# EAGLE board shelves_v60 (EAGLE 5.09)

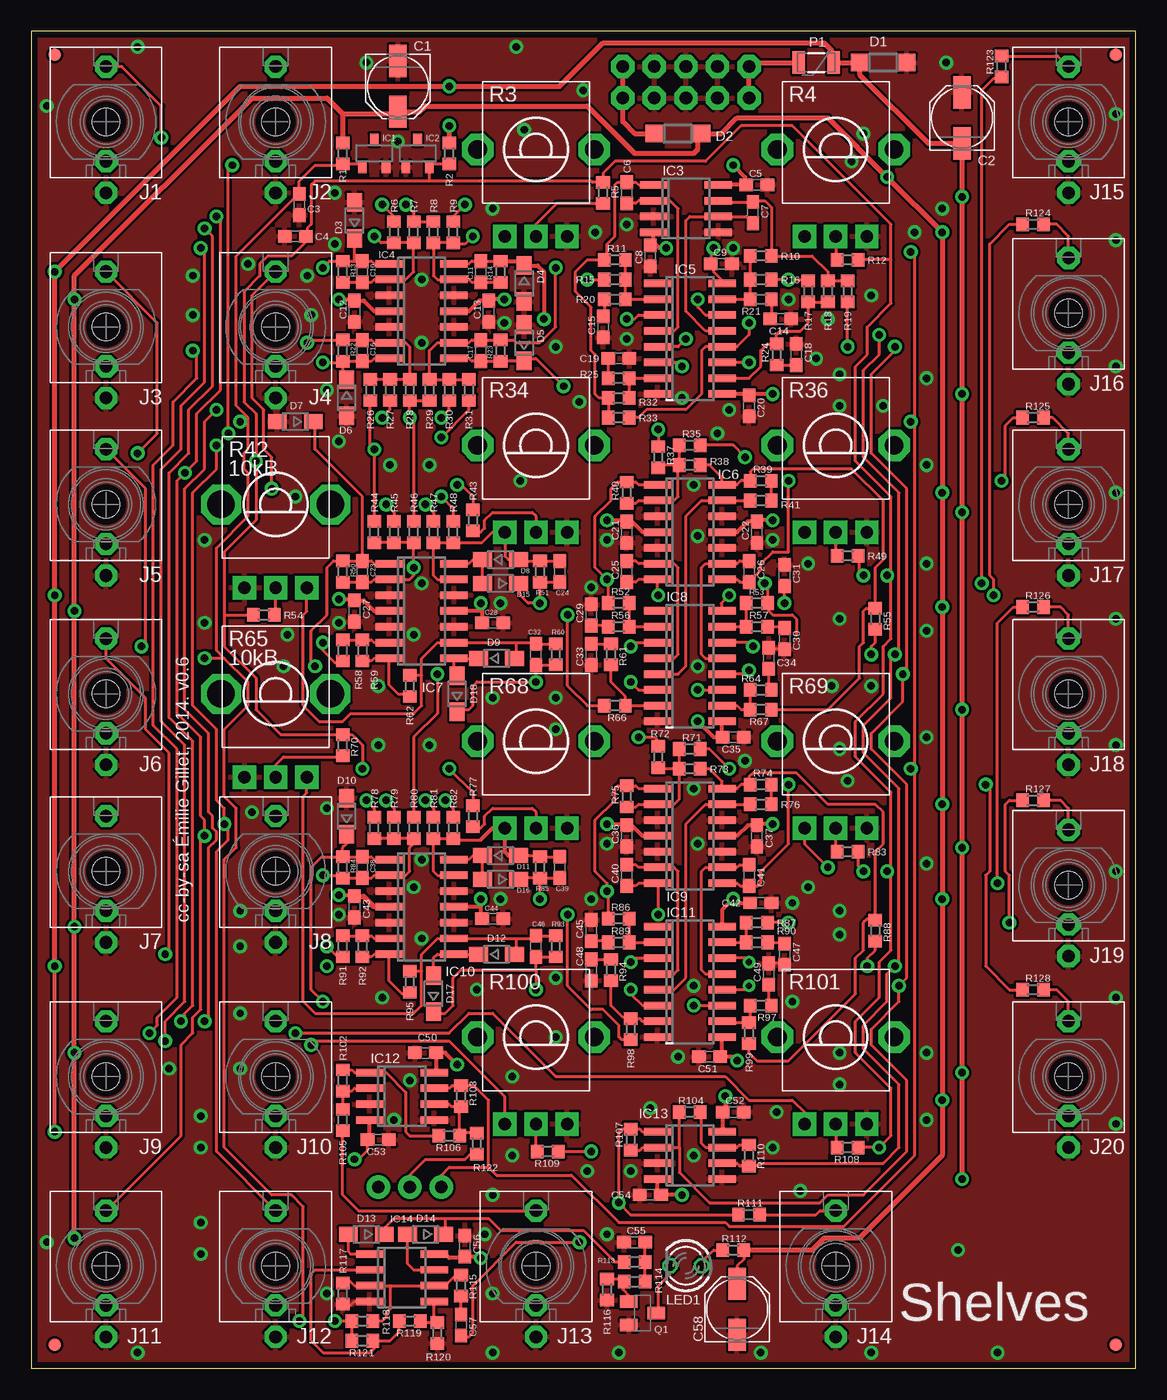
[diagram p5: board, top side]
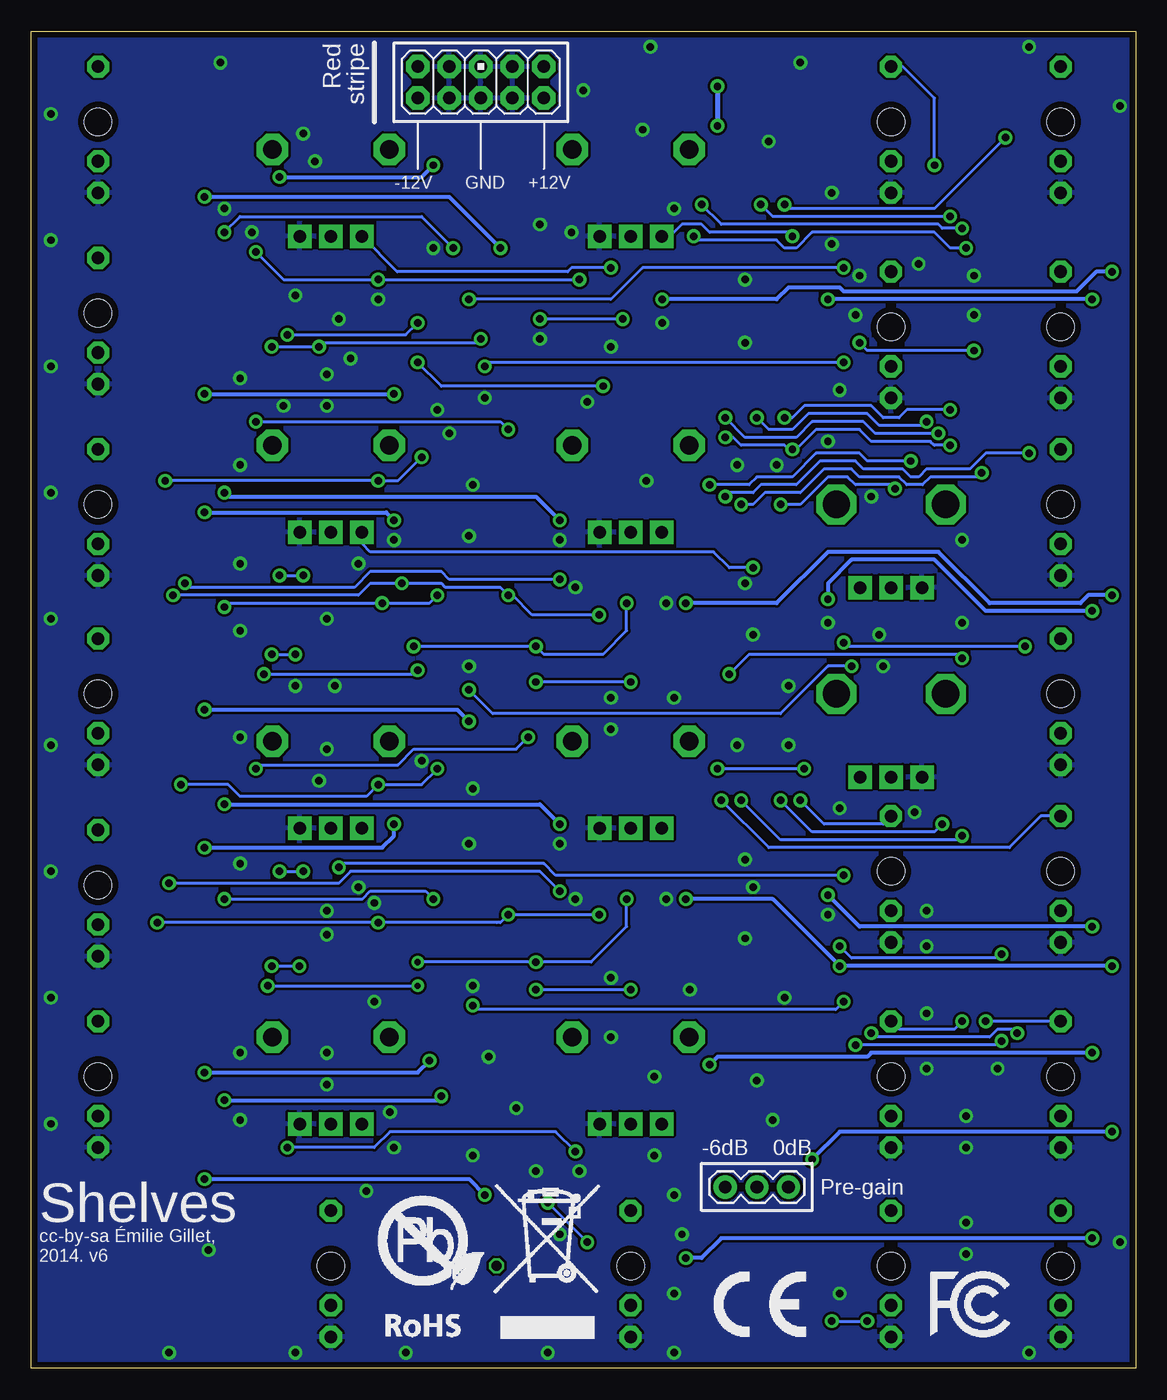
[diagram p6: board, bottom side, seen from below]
Size 88.9 x 107.63 mm. Coordinates in mm from the lower left corner, seen from the top.
Outline: 0,0 88.9,0 88.9,107.63 0,107.63 0,0
Copper layers (1*16): Top 0.035mm / dielectric 1.5mm / Bottom 0.035mm
Design rules "PCBCart-Standard": minimum track width 8mil, minimum drill 0.4mm, track to track 8mil, track to pad 8mil, pad to pad 8mil, via to via 8mil, smd to smd 8mil, copper to edge 20mil, drill to drill 8mil, minimum pad ring 8mil, minimum via ring 10mil, stop-mask expansion 3mil, vias tented up to drill 25mil, thermal gap 8mil

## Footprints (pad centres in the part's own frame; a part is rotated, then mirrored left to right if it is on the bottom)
PANASONIC_C = smd 2.6 x 1.4: + 2.05,0; - -2.05,0
C0603 = smd 1.1 x 1: 1 -0.85,0; 2 0.85,0
SOD123 = smd 1.4 x 1.4: A 1.9,0; C -1.9,0
SOD323-W = smd 1.5 x 1.2: A 1.45,0; C -1.45,0
DBZ_R-PDSO-G3 = smd 0.7 x 1: 1 -0.95,-1.1; 2 0.95,-1.1; 3 0,1.1
SO08 = smd 0.6 x 2.2: 1 -1.905,-2.6; 2 -0.635,-2.6; 3 0.635,-2.6; 4 1.905,-2.6; 5 1.905,2.6; 6 0.635,2.6; 7 -0.635,2.6; 8 -1.905,2.6
SO14 = smd 0.6 x 2.2: 1 -3.81,-2.6; 2 -2.54,-2.6; 3 -1.27,-2.6; 4 0,-2.6; 5 1.27,-2.6; 6 2.54,-2.6; 7 3.81,-2.6; 8 3.81,2.6; 9 2.54,2.6; 10 1.27,2.6; 11 0,2.6; 12 -1.27,2.6; 13 -2.54,2.6; 14 -3.81,2.6
SOIC16N = smd 0.6 x 2.2: 1 -4.445,-2.6; 2 -3.175,-2.6; 3 -1.905,-2.6; 4 -0.635,-2.6; 5 0.635,-2.6; 6 1.905,-2.6; 7 3.175,-2.6; 8 4.445,-2.6; 9 4.445,2.6; 10 3.175,2.6; 11 1.905,2.6; 12 0.635,2.6; 13 -0.635,2.6; 14 -1.905,2.6; 15 -3.175,2.6; 16 -4.445,2.6
WQP_PJ_301M6 = drill 1.016 pad 1.778 octagon: P1 0,-5.715; P2 0,-3.175; P3 0,4.445 | hole 2.2: 0,0
FIDUCIAL-1X2 = smd 1 x 1: 1 0,0
1X03 = drill 1.016 pad 1.88 round: 1 0,0; 2 2.54,0; 3 5.08,0
AVR_ICSP = drill 1.016 pad 1.88 octagon: 1 -1.27,5.08; 2 1.27,5.08; 3 -1.27,2.54; 4 1.27,2.54; 5 -1.27,0; 6 1.27,0; 7 -1.27,-2.54; 8 1.27,-2.54; 9 -1.27,-5.08; 10 1.27,-5.08
LED3MM = drill 0.813 octagon: A -1.27,0; K 1.27,0
PTC-1206 = smd 1 x 1.8: 1 -1.4,0; 2 1.4,0
SOT23-BEC = smd 1 x 1.4: B -0.95,-1.1; C 0,1.1; E 0.95,-1.1
R0603 = smd 1 x 1.1: 1 -0.85,0; 2 0.85,0
ALPS_POT_VERTICAL_PS = drill 1 pad 1.88 square: P$1 -2.5,7; P$2 0,7; P$3 2.5,7 | drill 1.5 pad 2.54 octagon: P$4 -4.7,0; P$5 4.7,0
ALPS_POT_VERTICAL = drill 1 pad 1.88 square: P$1 -2.5,6.7; P$2 0,6.7; P$3 2.5,6.7 | drill 2.2 pad 3.175 octagon: P$4 -4.4,0; P$5 4.4,0

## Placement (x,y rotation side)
C1  22u  [PANASONIC_C]  29.53,103.19 270 top
C2  22u  [PANASONIC_C]  74.93,100.65 90 top
C3  100n  [C0603]  21.59,93.66 270 top
C4  100n  [C0603]  21.27,91.12 180 top
C5  100n  [C0603]  58.42,95.25 0 top
C6  68p  [C0603]  47.94,94.61 90 top
C7  68p  [C0603]  58.1,93.03 90 top
C8  100n  [C0603]  49.85,89.53 90 top
C9  100n  [C0603]  55.56,88.9 0 top
C10  560p  [C0603]  26.67,88.27 270 top
C11  560p  [C0603]  36.2,88.27 270 top
C12  100n  [C0603]  26.04,85.09 270 top
C13  100n  [C0603]  36.83,85.09 90 top
C14  560p  [C0603]  60.33,84.45 0 top
C15  560p  [C0603]  46.04,83.82 270 top
C16  560p  [C0603]  26.67,81.92 90 top
C17  560p  [C0603]  36.2,81.92 90 top
C18  560p  [C0603]  61.59,81.6 90 top
C19  560p  [C0603]  47.31,81.28 0 top
C20  100n  [C0603]  57.79,77.47 90 top
C21  100n  [C0603]  47.94,67.31 270 top
C22  100n  [C0603]  58.42,67.31 90 top
C23  560p  [C0603]  26.67,64.14 270 top
C24  560p  [C0603]  42.55,64.14 90 top
C25  68p  [C0603]  47.94,64.14 270 top
C26  68p  [C0603]  57.79,64.14 270 top
C27  100n  [C0603]  26.04,60.96 270 top
C28  100n  [C0603]  37.15,60.01 180 top
C29  560p  [C0603]  45.09,60.64 90 top
C30  560p  [C0603]  60.64,58.74 270 top
C31  100n  [C0603]  60.64,63.82 90 top
C32  560p  [C0603]  40.64,57.47 90 top
C33  560p  [C0603]  45.09,57.47 270 top
C34  560p  [C0603]  59.37,57.15 90 top
C35  100n  [C0603]  56.52,50.8 180 top
C36  100n  [C0603]  47.94,42.86 270 top
C37  100n  [C0603]  58.42,42.86 90 top
C38  560p  [C0603]  26.67,40.32 270 top
C39  560p  [C0603]  42.55,40.32 90 top
C40  68p  [C0603]  47.94,39.69 270 top
C41  68p  [C0603]  57.79,39.69 270 top
C42  100n  [C0603]  58.74,37.47 0 top
C43  100n  [C0603]  26.04,37.15 270 top
C44  100n  [C0603]  37.15,36.2 180 top
C45  560p  [C0603]  45.09,35.24 90 top
C46  560p  [C0603]  40.64,33.97 90 top
C47  560p  [C0603]  60.64,33.34 270 top
C48  560p  [C0603]  45.09,32.07 270 top
C49  560p  [C0603]  59.37,31.75 90 top
C50  100n  [C0603]  31.75,25.4 180 top
C51  100n  [C0603]  54.61,25.08 0 top
C52  100n  [C0603]  56.52,20.64 0 top
C53  100n  [C0603]  27.94,18.41 180 top
C54  100n  [C0603]  49.85,13.97 0 top
C55  100n  [C0603]  48.58,10.16 180 top
C56  100n  [C0603]  34.93,9.84 90 top
C57  100n  [C0603]  34.61,3.49 270 top
C58  22u  [PANASONIC_C]  56.83,4.76 90 top
D1  1N5819HW  [SOD123]  68.58,105.09 180 top
D2  1N5819HW  [SOD123]  52.07,99.38 180 top
D3  1N4148  [SOD323-W]  26.04,92.39 90 top
D4  1N4148  [SOD323-W]  39.69,87.31 270 top
D5  1N4148  [SOD323-W]  39.69,82.55 90 top
D6  1N4148  [SOD323-W]  25.4,78.11 270 top
D7  1N4148  [SOD323-W]  21.27,76.2 180 top
D8  1N4148  [SOD323-W]  37.78,65.09 0 top
D9  1N4148  [SOD323-W]  37.47,57.15 0 top
D10  1N4148  [SOD323-W]  25.4,44.45 90 top
D11  1N4148  [SOD323-W]  37.78,41.27 0 top
D12  1N4148  [SOD323-W]  37.47,33.34 0 top
D13  1N4148  [SOD323-W]  26.99,10.79 180 top
D14  1N4148  [SOD323-W]  31.75,10.79 180 top
D15  1N4148  [SOD323-W]  37.78,63.18 180 top
D16  1N4148  [SOD323-W]  37.78,39.37 180 top
D17  1N4148  [SOD323-W]  32.38,30.16 90 top
D18  1N4148  [SOD323-W]  34.29,54.29 90 top
IC1  LM4040B10  [DBZ_R-PDSO-G3]  27.62,97.79 0 top
IC2  LM4040B10  [DBZ_R-PDSO-G3]  31.12,97.79 0 top
IC3  TL072D  [SO08]  52.7,93.34 270 top
IC4  TL074D  [SO14]  31.43,85.09 270 top
IC5  V2164SZ  [SOIC16N]  53.02,82.87 270 top
IC6  TL074D  [SO14]  53.02,67.31 270 top
IC7  TL074D  [SO14]  31.43,60.96 270 top
IC8  V2164SZ  [SOIC16N]  53.02,56.52 270 top
IC9  TL074D  [SO14]  53.02,42.86 270 top
IC10  TL074D  [SO14]  31.43,37.15 270 top
IC11  V2164SZ  [SOIC16N]  53.02,31.11 270 top
IC12  TL072D  [SO08]  29.85,21.91 270 top
IC13  TL072D  [SO08]  53.02,17.14 270 top
IC14  TL072D  [SO08]  29.85,7.3 270 top
J1  PJ301_THONKICONN6  [WQP_PJ_301M6]  6.03,100.33 0 top
J2  PJ301_THONKICONN6  [WQP_PJ_301M6]  19.69,100.33 0 top
J3  PJ301_THONKICONN6  [WQP_PJ_301M6]  6.03,83.82 0 top
J4  PJ301_THONKICONN6  [WQP_PJ_301M6]  19.69,83.82 0 top
J5  PJ301_THONKICONN6  [WQP_PJ_301M6]  6.03,69.53 0 top
J6  PJ301_THONKICONN6  [WQP_PJ_301M6]  6.03,54.29 0 top
J7  PJ301_THONKICONN6  [WQP_PJ_301M6]  6.03,40.01 0 top
J8  PJ301_THONKICONN6  [WQP_PJ_301M6]  19.69,40.01 0 top
J9  PJ301_THONKICONN6  [WQP_PJ_301M6]  6.03,23.5 0 top
J10  PJ301_THONKICONN6  [WQP_PJ_301M6]  19.69,23.5 0 top
J11  PJ301_THONKICONN6  [WQP_PJ_301M6]  6.03,8.26 0 top
J12  PJ301_THONKICONN6  [WQP_PJ_301M6]  19.69,8.26 0 top
J13  PJ301_THONKICONN6  [WQP_PJ_301M6]  40.64,8.26 0 top
J14  PJ301_THONKICONN6  [WQP_PJ_301M6]  64.77,8.26 0 top
J15  PJ301_THONKICONN6  [WQP_PJ_301M6]  83.5,100.33 0 top
J16  PJ301_THONKICONN6  [WQP_PJ_301M6]  83.5,84.93 0 top
J17  PJ301_THONKICONN6  [WQP_PJ_301M6]  83.5,69.53 0 top
J18  PJ301_THONKICONN6  [WQP_PJ_301M6]  83.5,54.29 0 top
J19  PJ301_THONKICONN6  [WQP_PJ_301M6]  83.5,38.89 0 top
J20  PJ301_THONKICONN6  [WQP_PJ_301M6]  83.5,23.5 0 top
JP1  FIDUCIAL1X2  [FIDUCIAL-1X2]  1.91,105.73 0 top
JP2  FIDUCIAL1X2  [FIDUCIAL-1X2]  87.31,105.73 0 top
JP3  FIDUCIAL1X2  [FIDUCIAL-1X2]  1.91,1.91 0 top
JP4  FIDUCIAL1X2  [FIDUCIAL-1X2]  87.31,1.91 0 top
JP5  [1X03]  27.94,14.61 180 bottom
JP11  M05X2PTH  [AVR_ICSP]  52.7,103.5 270 bottom
LED1  WP-710A10GD  [LED3MM]  52.7,8.26 180 top
P1  PTCSMD  [PTC-1206]  63.18,105.09 180 top
Q1  MMBT3904  [SOT23-BEC]  49.21,4.45 270 top
R1  3.3k  [R0603]  25.08,97.79 270 top
R2  1.0k  [R0603]  33.66,97.79 270 top
R3  10kB  [ALPS_POT_VERTICAL_PS]  40.64,98.11 180 top
R4  10kB  [ALPS_POT_VERTICAL_PS]  64.77,98.11 180 top
R5  100k  [R0603]  46.04,94.61 270 top
R6  100k  [R0603]  29.21,91.44 270 top
R7  100k  [R0603]  30.8,91.44 270 top
R8  100k  [R0603]  32.38,91.44 270 top
R9  100k  [R0603]  33.97,91.44 270 top
R10  100k  [R0603]  58.74,89.53 0 top
R11  100k  [R0603]  46.99,89.22 180 top
R12  100k  [R0603]  65.72,89.22 180 top
R13  18k  [R0603]  25.08,88.27 90 top
R14  18k  [R0603]  37.78,88.27 90 top
R15  100k  [R0603]  46.99,87.63 0 top
R16  100k  [R0603]  58.74,87.63 180 top
R17  100k  [R0603]  62.55,86.68 270 top
R18  100k  [R0603]  64.13,86.68 270 top
R19  100k  [R0603]  65.72,86.68 270 top
R20  510  [R0603]  46.99,86.04 0 top
R21  510  [R0603]  58.74,86.04 180 top
R22  12k  [R0603]  25.08,81.92 270 top
R23  12k  [R0603]  37.78,81.92 270 top
R24  510  [R0603]  60.01,81.6 90 top
R25  510  [R0603]  47.31,79.69 0 top
R26  120k  [R0603]  27.3,78.74 90 top
R27  120k  [R0603]  28.89,78.74 90 top
R28  200k  [R0603]  30.48,78.74 90 top
R29  200k  [R0603]  32.07,78.74 90 top
R30  120k  [R0603]  33.66,78.74 90 top
R31  120k  [R0603]  35.24,78.74 90 top
R32  100k  [R0603]  47.31,78.11 0 top
R33  100k  [R0603]  47.31,76.52 0 top
R34  10kB  [ALPS_POT_VERTICAL_PS]  40.64,74.3 180 top
R35  100k  [R0603]  53.02,74.3 0 top
R36  10kB  [ALPS_POT_VERTICAL_PS]  64.77,74.3 180 top
R37  100k  [R0603]  50.48,73.34 270 top
R38  100k  [R0603]  53.02,72.71 0 top
R39  100k  [R0603]  58.74,71.44 0 top
R40  100k  [R0603]  47.94,70.48 90 top
R41  100k  [R0603]  58.74,69.85 180 top
R42  10kB  [ALPS_POT_VERTICAL]  19.69,69.53 180 top
R43  100k  [R0603]  35.56,68.26 270 top
R44  120k  [R0603]  27.62,67.31 270 top
R45  120k  [R0603]  29.21,67.31 270 top
R46  200k  [R0603]  30.8,67.31 270 top
R47  100k  [R0603]  32.38,67.31 270 top
R48  100k  [R0603]  33.97,67.31 270 top
R49  100k  [R0603]  65.72,65.41 180 top
R50  12k  [R0603]  25.08,64.14 90 top
R51  18k  [R0603]  40.96,64.14 270 top
R52  100k  [R0603]  47.31,61.59 0 top
R53  100k  [R0603]  58.42,61.59 180 top
R54  150k  [R0603]  18.73,60.64 0 top
R55  100k  [R0603]  67.94,60.33 270 top
R56  510  [R0603]  47.31,59.69 0 top
R57  510  [R0603]  58.42,59.69 180 top
R58  100k  [R0603]  25.08,57.78 90 top
R59  100k  [R0603]  26.67,57.78 270 top
R60  22k  [R0603]  42.23,57.47 270 top
R61  510  [R0603]  46.67,57.47 270 top
R62  150k  [R0603]  30.48,54.93 90 top
R64  510  [R0603]  58.74,54.61 180 top
R65  10kB  [ALPS_POT_VERTICAL]  19.69,54.29 180 top
R66  100k  [R0603]  46.99,53.34 0 top
R67  100k  [R0603]  58.74,53.02 180 top
R68  10kB  [ALPS_POT_VERTICAL_PS]  40.64,50.48 180 top
R69  10kB  [ALPS_POT_VERTICAL_PS]  64.77,50.48 180 top
R70  150k  [R0603]  25.08,50.16 270 top
R71  100k  [R0603]  53.02,49.85 0 top
R72  100k  [R0603]  50.48,49.21 270 top
R73  100k  [R0603]  53.02,48.26 0 top
R74  100k  [R0603]  58.74,46.99 0 top
R75  100k  [R0603]  47.94,46.04 90 top
R76  100k  [R0603]  58.74,45.4 180 top
R77  100k  [R0603]  35.56,44.45 270 top
R78  120k  [R0603]  27.62,43.5 270 top
R79  120k  [R0603]  29.21,43.5 270 top
R80  200k  [R0603]  30.8,43.5 270 top
R81  100k  [R0603]  32.38,43.5 270 top
R82  100k  [R0603]  33.97,43.5 270 top
R83  100k  [R0603]  65.72,41.59 180 top
R84  12k  [R0603]  25.08,40.32 90 top
R85  18k  [R0603]  40.96,40.32 270 top
R86  100k  [R0603]  47.31,36.2 0 top
R87  100k  [R0603]  58.42,35.88 180 top
R88  100k  [R0603]  67.94,35.24 270 top
R89  510  [R0603]  47.31,34.29 0 top
R90  510  [R0603]  58.42,34.29 180 top
R91  100k  [R0603]  25.08,33.97 90 top
R92  100k  [R0603]  26.67,33.97 270 top
R93  22k  [R0603]  42.23,33.97 270 top
R94  510  [R0603]  46.67,32.07 270 top
R95  150k  [R0603]  30.48,31.11 90 top
R97  510  [R0603]  58.74,29.21 180 top
R98  100k  [R0603]  48.26,27.3 90 top
R99  100k  [R0603]  57.79,26.99 90 top
R100  10kB  [ALPS_POT_VERTICAL_PS]  40.64,26.67 180 top
R101  10kB  [ALPS_POT_VERTICAL_PS]  64.77,26.67 180 top
R102  100k  [R0603]  25.08,23.18 90 top
R103  100k  [R0603]  34.61,21.91 90 top
R104  100k  [R0603]  53.02,20.64 180 top
R105  100k  [R0603]  25.08,20 90 top
R106  200k  [R0603]  33.66,18.73 0 top
R107  200k  [R0603]  48.26,18.41 90 top
R108  100k  [R0603]  65.72,17.78 180 top
R109  100k  [R0603]  41.59,17.46 180 top
R110  100k  [R0603]  57.79,17.14 90 top
R111  1.0k  [R0603]  57.79,12.38 0 top
R112  1.0k  [R0603]  56.52,9.53 0 top
R113  12k  [R0603]  48.58,8.57 0 top
R114  100k  [R0603]  48.58,6.99 180 top
R115  100k  [R0603]  34.61,6.67 90 top
R116  22k  [R0603]  46.36,6.35 90 top
R117  100k  [R0603]  25.08,6.03 90 top
R118  100k  [R0603]  26.67,3.81 180 top
R119  220k  [R0603]  30.48,3.81 180 top
R120  100k  [R0603]  32.7,2.86 90 top
R121  100k  [R0603]  26.67,2.22 180 top
R122  100k  [R0603]  35.88,18.1 270 top
R123  1.0k  [R0603]  78.1,104.78 90 top
R124  1.0k  [R0603]  80.64,92.08 0 top
R125  1.0k  [R0603]  80.64,76.52 0 top
R126  1.0k  [R0603]  80.64,61.28 0 top
R127  1.0k  [R0603]  80.64,45.72 0 top
R128  1.0k  [R0603]  80.64,30.48 0 top
U$1  [FCC_MEDIUM]  16.51,2.54 0 bottom
U$2  [ROHS_BIG]  62.23,1.59 0 bottom
U$3  [CE_MEDIUM]  33.97,2.54 0 bottom

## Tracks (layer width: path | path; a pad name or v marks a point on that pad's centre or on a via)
AREF_+10  (via drill 0.6)
  Top 0.254: 17.46,76.2 17.46,76.52 16.51,77.47 16.51,89.53 21.49,94.51 C3.1 21.59,95.57 22.86,96.84 24.76,96.84 24.87,96.94 R1.2 26.42,96.94 IC1.1 | 15.56,57.15 17.46,55.24 17.46,53.34 15.56,51.44 15.56,46.04 16.51,45.09 16.51,41.91 15.56,40.96 15.56,17.78 19.37,13.97 20.96,13.97 21.91,13.02 21.91,4.13 v21.59,3.81 | 15.56,57.15 14.92,57.78 14.92,66.04 17.46,68.58 17.46,72.07 17.15,72.39 17.15,73.66 17.46,73.98 17.46,76.2 | R29.1 R28.1 v30.48,76.52 30.8,76.2 R46.1 | 17.46,76.2 v16.83,76.2 | 15.56,57.15 v13.97,57.15 | R121.2 R118.2 v24.45,3.81 | R80.1 30.8,50.8 32.7,52.7 v32.7,55.88
  Bottom 0.254: v30.48,76.52 29.53,75.56 27.62,75.56 26.35,76.83 21.59,76.83 20.64,75.88 17.15,75.88 v16.83,76.2 | v13.97,57.15 14.29,57.47 31.12,57.47 v32.7,55.88 | v24.45,3.81 v21.59,3.81
AREF_-10  (via drill 0.6)
  Top 0.254: R108.1 v68.26,17.78 69.21,18.73 69.21,22.54 66.36,25.4 66.36,27.94 68.26,29.84 68.26,32.7 69.21,33.66 69.21,40.01 | 69.21,40.01 69.21,46.35 66.36,49.21 66.36,52.07 68.58,54.29 68.58,58.1 69.21,58.74 69.21,63.82 | 69.21,63.82 69.21,70.17 66.36,73.03 66.36,80.64 67.31,81.6 67.31,83.82 69.21,85.72 69.21,89.22 | 69.21,89.22 69.21,92.08 61.28,100.01 57.15,100.01 54.29,97.16 46.99,97.16 46.04,96.2 R5.1 45.19,95.47 45.08,95.57 32.07,95.57 | 69.21,89.22 R12.1 | R49.1 66.68,65.3 66.68,64.14 v66.99,63.82 | 69.21,63.82 v68.9,63.82 | 66.68,41.49 R83.1 66.57,40.42 v66.99,40.01 | 69.21,40.01 v68.9,40.01 | 15.56,60.64 15.56,58.1 18.1,55.56 18.1,53.02 20.1,51.02 R70.1 | 15.56,60.64 15.56,65.72 18.1,68.26 v18.1,73.03 18.1,76.83 17.15,77.79 17.15,86.68 18.42,87.95 18.42,88.9 19.05,89.53 20.96,89.53 22.12,90.7 C4.1 22.22,91.22 22.22,91.76 22.54,92.08 22.54,95.25 22.86,95.57 32.07,95.57 | 15.56,60.64 R54.1 | R70.1 24.98,51.12 | v26.67,48.26 26.67,50.16 25.82,51.02 R70.1 | R109.1 v45.08,17.46 | R77.1 35.56,46.35 v33.65,48.26 | v34.29,71.12 34.61,71.12 35.56,70.17 R43.1 | 32.07,95.57 IC2.2 32.32,96.94 R2.2
  Bottom 0.254: v68.9,63.82 v66.99,63.82 | v68.9,40.01 v66.99,40.01 | v34.29,71.12 31.12,71.12 30.48,71.75 27.62,71.75 25.72,73.66 22.22,73.66 21.59,73.03 v18.1,73.03 | v26.67,48.26 v33.65,48.26 | v45.08,17.46 46.67,19.05 60.01,19.05 61.28,17.78 v68.26,17.78
BP_1  (via drill 0.6)
  Top 0.254: v50.48,36.51 50.48,38.99 IC9.7 48.9,39.05 48.68,38.84 C40.2 | v60.96,35.88 R87.1 | R98.1 47.52,26.45 47.31,26.67 47.31,27.62 46.04,28.89 45.08,28.89 43.18,30.8 v43.18,36.51 | v78.74,35.88 78.74,39.69 78.42,40.01 78.42,45.4 78.74,45.72 R127.1
  Bottom 0.254: v43.18,36.51 v50.48,36.51 51.12,35.88 51.44,35.88 v60.96,35.88 v78.74,35.88
BP_2  (via drill 0.6)
  Top 0.254: C25.2 48.68,63.28 48.9,63.5 IC6.7 50.42,62.29 v50.48,62.23 | R66.1 44.77,53.34 43.18,54.93 v43.18,60.64 | v59.05,63.18 59.27,62.97 R53.1 59.37,61.49 59.37,60.96 59.69,60.64 61.28,60.64 61.59,60.33 61.59,59.05 | v77.47,62.23 77.47,63.5 77.15,63.82 77.15,90.49 78.74,92.08 R124.1
  Bottom 0.254: v43.18,60.64 48.58,60.64 50.16,62.23 v50.48,62.23 51.12,62.87 55.56,62.87 55.88,63.18 v59.05,63.18 61.59,63.18 62.55,62.23 v77.47,62.23
F_GLOBAL  (via drill 0.6)
  Top 0.254: R8.1 R7.1 30.8,93.03 v30.16,93.66 | v14.92,92.71 15.24,92.39 15.24,78.74 13.33,76.83 13.33,73.03 v12.38,72.07 11.75,71.44 11.75,52.7 13.65,50.8 13.65,44.45 13.97,44.13 v13.97,42.86 13.65,42.55 13.65,28.89 13.02,28.26 13.02,26.99 12.06,26.04 12.06,18.73 J11.P3 | v31.75,69.53 32.38,68.9 R47.1 | v31.75,45.72 32.38,45.09 R81.1
  Bottom 0.254: v30.16,93.66 29.21,92.71 v14.92,92.71 | v12.38,72.07 12.7,71.75 16.51,71.75 17.15,71.12 18.42,71.12 19.05,71.75 22.22,71.75 22.86,72.39 25.08,72.39 26.99,70.48 29.85,70.48 30.8,69.53 v31.75,69.53 | v31.75,45.72 28.58,42.55 14.29,42.55 v13.97,42.86
GAIN_GLOBAL  (via drill 0.6)
  Top 0.254: J12.P3 14.92,17.46 14.92,41.59 15.87,42.55 15.87,43.5 v15.56,43.81 15.56,45.09 14.92,45.72 14.92,51.44 13.02,53.34 13.02,70.48 14.92,72.39 v14.92,74.3 | R31.1 35.24,77.15 v33.02,74.93 | R26.1 27.3,74.3 v27.62,73.98 R44.1 | v28.58,45.72 29.21,45.09 R79.1
  Bottom 0.254: v14.92,74.3 16.19,74.3 16.51,74.61 21.27,74.61 22.22,75.56 25.72,75.56 27.3,73.98 v27.62,73.98 27.94,73.98 28.26,74.3 31.75,74.3 32.38,74.93 v33.02,74.93 | v28.58,45.72 26.03,43.18 16.19,43.18 v15.56,43.81
GND  (via drill 0.6)
  Top 0.254: C47.2 60.53,32.6 C49.2 | C34.2 59.48,57.89 C30.2 | R117.1 25.19,5.08 25.72,5.08 26.03,5.4 IC14.4
  other vias: 56.52,90.17 60.96,86.04 47.94,92.08 47.94,82.87 46.36,66.67 53.34,71.12 59.69,66.67 56.2,77.15 52.39,78.11 46.36,42.23 57.47,48.9 53.34,46.67 45.09,62.87 45.09,37.78 61.28,29.53 48.26,15.88 60.01,20.64 53.34,17.14 63.18,81.28 29.53,98.74 38.1,84.14 31.43,82.55 24.45,94.61 42.23,82.23 64.13,84.45 44.13,77.79 24.77,74.61 23.81,78.74 21.27,70.17 24.77,60.01 52.07,25.08 67.63,54.93 65.09,49.85 42.23,53.98 31.43,63.18 30.8,59.05 31.43,87.63 24.77,36.51 29.21,20 30.48,23.18 45.4,91.44 37.15,93.34 13.02,87.95 13.02,84.77 22.54,84.77 13.97,66.67 13.97,60.01 20.64,59.05 20.32,56.52 23.81,45.09 17.78,44.77 16.83,36.83 27.94,50.16 16.83,28.57 38.73,23.5 11.11,24.13 35.88,30.48 42.23,26.67 42.23,31.43 53.34,30.8 53.66,42.23 42.23,51.44 53.66,66.99 53.66,56.52 28.89,72.71 32.07,72.71 39.37,71.44 39.69,99.69 44.45,102.87 68.58,77.47 66.99,99.38 59.69,17.78 38.73,17.14 37.15,13.97 13.65,17.78 13.65,20.32 16.83,24.13 23.81,6.03 36.51,10.79 37.15,6.03 13.65,9.21 32.07,50.16 37.15,53.98 24.45,90.49 28.26,29.84 31.43,40.96 44.77,15.88 16.83,33.97 30.8,38.73 31.43,34.61 65.09,77.47 65.09,80.01 55.25,75.25 65.09,22.86 65.09,25.4 61.91,14.29 27.94,54.93 65.72,47.31 22.23,87.95 13.65,11.75 49.85,20.95 1.27,101.6 8.57,1.27 37.15,1.27 47.31,1.27 58.74,1.27 67.63,1.27 74.61,9.53 8.57,106.36 46.36,10.79 66.04,97.16 1.27,10.16 39.05,106.36 61.28,37.47 62.55,64.77 64.45,54.93 37.78,37.78 37.78,61.59 17.46,88.9 73.34,93.34 26.99,105.09 77.79,1.27 87.31,19.68 87.31,29.84 87.31,40.01 87.31,50.16 87.31,60.33 87.31,70.48 87.31,80.64 87.31,90.81 87.31,100.97 73.66,105.09 67.63,86.36 65.09,60.33 65.09,36.83 65.09,34.92 62.55,38.73 72.07,20 72.07,25.4 72.07,40.64 72.07,50.8 72.07,59.37 72.07,64.77 72.07,72.71 72.07,79.69 71.12,91.44
  pour Bottom: 0,107.63 0,0 88.9,0 88.9,107.63
  pour Top (isolate 0.203): 0,107.63 0,0 88.9,0 88.9,107.63
HP_1  (via drill 0.6)
  Top 0.254: IC9.1 48.9,46.67 48.68,46.89 R75.2 47.2,46.89 46.99,46.67 46.99,45.72 45.4,44.13 45.4,40.01 46.36,39.05 v46.36,38.42 46.46,38.31 R86.1 | v77.79,39.05 77.79,60.01 79.06,61.28 R126.1
  Bottom 0.254: v46.36,38.42 47.94,40.01 63.18,40.01 64.13,39.05 v77.79,39.05
HP_2  (via drill 0.6)
  Top 0.254: IC6.1 48.9,71.12 48.68,71.33 R40.2 | R40.2 47.52,71.33 | R40.2 47.2,71.33 46.67,70.8 46.67,69.85 45.4,68.58 45.4,64.45 v46.36,63.5 46.46,63.4 R52.1 | R123.1 78,103.82 77.47,103.82 76.52,102.87 v76.52,63.18
  Bottom 0.254: v46.36,63.5 55.25,63.5 55.88,64.14 61.59,64.14 62.87,62.87 76.2,62.87 v76.52,63.18
IN  (via drill 0.6)
  Top 0.254: v44.77,87.63 R15.1 | R16.1 v60.96,87.63 62.44,87.63 R17.1 | IC12.7 33.65,22.54 33.87,22.76 R103.2 | R103.2 34.71,22.86 | 71.12,48.26 71.12,17.14 65.41,11.43 56.2,11.43 55.88,11.75 47.31,11.75 43.5,15.56 37.47,15.56 36.83,16.19 | 71.12,48.26 v70.8,48.26 | 71.12,48.26 71.12,76.2 | 71.12,76.2 v70.8,76.2 | 71.12,76.2 71.12,89.53 v70.8,89.85 | 50.38,74.3 R37.1 v50.48,75.56 | 50.27,49.85 R72.1 50.48,50.48 50.16,50.8 v48.9,50.8 | R103.2 35.66,22.76 36.83,21.59 36.83,16.19 | 36.83,16.19 33.65,16.19 33.02,15.56 JP5.3
  Bottom 0.254: v44.77,87.63 v60.96,87.63 68.58,87.63 v70.8,89.85 | v50.48,75.56 51.12,76.2 v70.8,76.2 | v48.9,50.8 49.85,49.85 58.1,49.85 59.37,48.58 70.49,48.58 v70.8,48.26
IN_INV
  Top 0.254: R102.2 25.82,24.03 26.03,23.81 IC12.1 28.58,23.81 30.16,22.23 30.16,19.05 30.48,18.73 R106.1
IN_INV1
  Top 0.254: R104.1 53.97,20.54 53.97,18.1 54.29,17.78 IC13.7 56.83,17.78 57.05,18 R110.2
J_HF_CV  (via drill 0.6)
  Top 0.254: v16.19,96.84 15.87,96.52 v15.87,75.25 | R30.1 33.65,77.15 v33.02,76.52
  Bottom 0.254: J2.P3 18.73,104.78 16.19,102.23 v16.19,96.84 | v33.02,76.52 31.43,74.93 27.3,74.93 26.03,76.2 21.91,76.2 20.96,75.25 v15.87,75.25
J_HF_F  (via drill 0.6)
  Top 0.254: v28.26,93.66 29.21,92.71 R6.1 | v10.48,99.06 10.48,101.6 7.3,104.78 J1.P3
  Bottom 0.254: v28.26,93.66 27.94,93.34 16.19,93.34 v10.48,99.06
J_IN
  Top 0.254: R105.1 25.08,13.97 26.35,12.7 J13.P3
J_LF_CV  (via drill 0.6)
  Top 0.254: v13.97,27.94 14.29,28.26 14.29,41.91 14.92,42.55 14.92,43.18 14.6,43.5 14.6,44.45 14.29,44.77 14.29,51.12 12.38,53.02 12.38,70.8 13.97,72.39 13.97,76.2 v14.92,77.15 | v28.26,76.52 28.89,77.15 R27.1
  Bottom 0.254: v13.97,27.94 14.6,27.3 19.05,27.3 J10.P3 | v14.92,77.15 18.42,77.15 19.05,76.52 20.32,76.52 21.27,77.47 26.67,77.47 27.62,76.52 v28.26,76.52
J_LF_F  (via drill 0.6)
  Top 0.254: v13.97,91.76 14.6,91.12 14.6,79.06 12.7,77.15 12.7,73.66 11.11,72.07 11.11,52.39 13.02,50.48 13.02,29.21 12.38,28.57 12.38,28.26 v12.06,27.94 | v34.93,93.66 33.97,92.71 R9.1
  Bottom 0.254: v34.93,93.66 33.34,92.08 15.87,92.08 15.56,91.76 v13.97,91.76 | J9.P3 v12.06,27.94
LP
  Top 0.254: IC3.1 50,95.15 49.85,95.3 49.8,95.25 48.9,95.25 48.68,95.47 C6.2 47.2,95.47 46.99,95.25 46.99,91.12 46.36,90.49 46.36,89.43 R11.2 44.77,89.22 43.82,88.27 43.82,86.68 45.08,85.41 45.08,81.92 45.4,81.6 45.4,78.42 45.72,78.11 R32.1 R33.1
LP1
  Top 0.254: IC3.7 55.41,93.88 C7.2 58.2,93.98 59.05,93.98 59.59,93.45 R10.2 62.87,89.53 64.13,88.27 R18.1 R19.1
MID1_F1  (via drill 0.6)
  Top 0.254: IC8.14 57.79,58.42 v58.1,58.1 | v48.26,58.1 48.58,58.42 IC8.3 | D15.C 39.37,63.05 39.37,62.23 40.01,61.59 v40.96,61.59 R51.2 C24.1
  Bottom 0.254: v58.1,58.1 v48.26,58.1 47.62,57.47 42.86,57.47 40.96,59.37 v40.96,61.59
MID1_F2  (via drill 0.5, 0.6)
  Top 0.254: IC11.3 48.58,33.02 v48.26,32.7 | IC11.14 57.47,33.02 v57.79,32.7 | R85.2 C39.1 | D16.C 39.33,39.47 R85.2 | v40.96,37.78 R85.2
  Bottom 0.254: v40.96,37.78 40.96,35.56 43.82,32.7 v48.26,32.7 v57.79,32.7
MINUS_BUS  (via drill 0.5, 0.6)
  Top 0.254: v69.53,82.23 69.53,81.92 67.63,80.01 67.63,73.66 70.49,70.8 70.49,56.2 v70.17,55.88 70.17,53.66 67.63,51.12 67.63,49.85 70.49,46.99 70.49,31.43 v69.85,30.8 69.85,29.53 67.63,27.3 67.63,26.04 70.49,23.18 70.49,17.46 66.99,13.97 64.13,13.97 63.5,13.34 54.61,13.34 52.17,15.77 52.17,17.78 | R19.2 65.82,85.72 65.72,85.62 v65.72,82.23 | IC8.12 57.47,55.88 v57.79,56.2 | v57.79,30.8 57.47,30.48 IC11.12 | R107.1 49,17.57 49.21,17.78 IC13.2 52.17,17.78 | 52.17,17.78 R104.2 | v52.7,82.87 52.07,82.23 IC5.5
  Bottom 0.254: v69.53,82.23 v65.72,82.23 65.41,82.55 53.02,82.55 v52.7,82.87 | v70.17,55.88 58.1,55.88 v57.79,56.2 | v69.85,30.8 v57.79,30.8
N$1
  Top 0.254: IC5.2 R20.2 R15.2 R11.1
N$2
  Top 0.254: R25.1 C19.1
N$3  (via drill 0.6)
  Top 0.254: IC4.14 35.24,88.9 35.46,89.11 C11.1 R14.2 38,88.9 | IC5.3 48.9,84.77 48.58,84.45 v47.94,84.45
  Top 0.305: R14.2 39.33,89.11 D4.C 40.78,88.76 41.27,88.27 v41.27,84.45
  Bottom 0.254: v41.27,84.45 v47.94,84.45
N$4
  Top 0.254: IC5.4 51.75,83.5 52.07,83.82 52.07,93.34 51.44,93.98 IC3.2 48.9,93.98 48.68,93.77 C6.1
N$5
  Top 0.254: C14.1 59.59,84.57 R21.1
N$6
  Top 0.254: JP5.2 30.48,15.56 31.75,16.83 34.93,16.83 35.34,17.25 R122.2
N$7  (via drill 0.6)
  Top 0.254: IC5.6 52.07,80.96 v52.39,80.64 | IC4.7 27.62,81.28 27.41,81.06 C16.1 R22.2 | D6.C 25.08,79.87 R22.2 | R22.2 24.98,80.96 v23.49,80.96
  Bottom 0.254: v23.49,80.96 52.07,80.96 v52.39,80.64
N$8
  Top 0.254: IC10.14 35.24,40.96 35.56,41.27 D11.C D16.A
N$9
  Top 0.254: IC12.2 26.03,22.54 25.82,22.33 R102.1 R105.2
N$10
  Top 0.254: C15.1 46.14,84.77 R20.1
N$11
  Top 0.254: R95.1 30.38,30.16 29.85,30.16 28.83,31.18 IC10.7 27.62,33.34 27.41,33.12 R92.2
N$12
  Top 0.254: R109.2 40.64,17.57 R100.P$2
N$13  (via drill 0.6)
  Top 0.254: R26.2 R27.2 R28.2 30.48,82.23 30.16,82.55 IC4.6 27.62,82.55 27.41,82.77 C16.2 R22.1 22.44,82.77 v22.22,82.55 | v13.02,81.92 13.33,81.6 13.33,79.69 11.43,77.79 11.43,74.3 9.84,72.71 9.84,51.75 11.75,49.85 11.75,29.84 10.16,28.26 10.16,27.62 v9.53,26.99 | R101.P$3 62.27,20.6 61.28,21.59 57.79,21.59 55.88,23.5 42.23,23.5 37.15,28.57 35.24,28.57 33.65,26.99 v21.27,26.99
  Bottom 0.254: v22.22,82.55 21.59,81.92 v13.02,81.92 | v9.53,26.99 9.84,27.3 11.11,27.3 11.75,26.67 20.96,26.67 v21.27,26.99
N$14
  Top 0.254: IC7.14 35.24,64.77 35.56,65.09 D8.C D15.A
N$15
  Top 0.254: R108.2 64.77,17.88 R101.P$2
N$16
  Top 0.254: 55.56,86.04 IC5.15 R21.2 R16.2 R10.1
N$17
  Top 0.254: R32.2 R25.2 IC5.7
N$18  (via drill 0.6)
  Top 0.254: R14.1 C11.2 35.46,87.42 35.24,87.63 IC4.13 32.7,87.63 32.38,87.95 R8.2 R9.2 34.08,90.49 34.93,90.49 v35.56,91.12 | v13.65,90.17 13.97,89.85 13.97,79.38 12.06,77.47 12.06,73.98 10.48,72.39 10.48,52.07 12.38,50.16 12.38,29.53 10.8,27.94 v10.8,26.35 | R100.P$3 38.1,19.71 38.1,21.91 33.65,26.35 22.86,26.35 v22.54,26.04
  Bottom 0.254: v13.65,90.17 14.92,90.17 16.19,91.44 26.03,91.44 27.3,90.17 28.26,90.17 28.89,90.81 35.24,90.81 v35.56,91.12 | v10.8,26.35 11.11,26.04 v22.54,26.04
N$19
  Top 0.254: C7.1 57.57,92.71 IC3.6 53.02,92.71 52.7,92.39 52.7,85.09 54.29,83.5 IC5.13
N$20
  Top 0.254: J19.P3 83.5,45.09 82.87,45.72 R127.2
N$21
  Top 0.254: R3.P$2 40.64,92.08 42.33,93.77 R5.2
N$22  (via drill 0.6)
  Top 0.254: v57.79,80.96 IC5.11 | IC4.8 35.24,81.28 35.46,81.06 C17.1 R23.2 37.82,81.1 D5.C 39.87,81.28 40.64,81.28 v42.86,79.06
  Bottom 0.254: v57.79,80.96 55.88,79.06 v42.86,79.06
N$23  (via drill 0.6)
  Top 0.254: v42.23,88.58 42.23,83.82 40.96,82.55 39.05,82.55 38.84,82.77 R23.1 C17.2 35.46,82.77 35.24,82.55 IC4.9 32.7,82.55 32.07,81.92 R29.2 R30.2 R31.2
  Bottom 0.254: R4.P$3 59.43,88.27 45.72,88.27 45.4,88.58 v42.23,88.58
N$24
  Top 0.254: R126.2 82.87,61.28 83.5,60.64 J18.P3
N$25
  Top 0.254: R89.1 46.36,34.39 C45.1
N$26
  Top 0.254: R12.2 64.77,89.32 R4.P$2
N$27  (via drill 0.6)
  Top 0.254: R13.1 C10.2 27.41,87.42 27.62,87.63 IC4.2 30.16,87.63 30.8,88.27 R7.2 R6.2 28.15,90.59 v27.62,91.12
  Bottom 0.254: 38.12,91.12 R3.P$3 37.48,91.11 36.51,92.08 34.93,92.08 34.29,91.44 27.94,91.44 v27.62,91.12
N$28
  Top 0.254: R24.1 C18.1
N$29
  Top 0.254: IC5.10 57.79,79.69 58.74,80.64 58.74,81.92 59.27,82.45 R24.2 60.01,83.19 60.33,83.5 61.91,83.5 62.55,84.14 R17.2 R18.2
N$30
  Top 0.254: IC12.6 33.65,21.27 33.87,21.06 R103.1 34.51,20.95 R106.2 34.72,18.95 R122.1
N$31  (via drill 0.6)
  Top 0.254: IC4.1 27.62,88.9 27.41,89.11 C10.1 26.03,89.11 | IC5.14 54.29,84.77 53.66,85.41 v53.66,86.04 | 26.03,89.11 R13.2 24.03,89.11 v23.49,88.58 | 26.03,89.11 D3.C
  Bottom 0.254: v23.49,88.58 39.69,88.58 42.23,86.04 v53.66,86.04
N$32  (via drill 0.6)
  Top 0.254: v33.34,45.72 33.97,45.09 R82.1
  Bottom 0.254: v33.34,45.72 29.53,41.91 10.16,41.91 7.62,44.45 J7.P3
N$33
  Top 0.254: R77.2 35.66,43.5 36.19,43.5 36.51,43.81 36.51,44.45 37.15,45.09 40.32,45.09 40.64,44.77 R68.P$2
N$34  (via drill 0.6)
  Top 0.254: IC10.1 27.62,40.96 27.41,41.17 C38.1 R84.2 | v53.34,29.21 IC11.11 | v23.49,29.53 22.54,30.48 22.54,40.32 23.39,41.17 R84.2 | R84.2 25.08,41.91 25.4,42.23 D10.C
  Bottom 0.254: v53.34,29.21 53.02,28.89 24.13,28.89 v23.49,29.53
N$35  (via drill 0.6)
  Top 0.254: R78.2 R79.2 R80.2 30.8,42.23 30.48,41.91 30.48,40.01 30.16,39.69 IC10.2 27.62,39.69 27.41,39.47 C38.2 R84.1 24.87,39.69 v23.49,39.69 | 62.23,43.44 R69.P$3 62.27,42.19 v64.13,40.32
  Bottom 0.254: v23.49,39.69 46.67,39.69 47.62,40.64 63.82,40.64 v64.13,40.32
N$36  (via drill 0.6)
  Top 0.254: R78.1 27.52,44.45 27.62,44.55 27.62,45.09 v26.99,45.72
  Bottom 0.254: v26.99,45.72 25.08,43.81 20.32,43.81 J8.P3
N$37
  Top 0.254: R83.2 64.77,41.7 R69.P$2
N$38
  Top 0.254: IC10.13 32.7,39.69 32.38,40.01 R81.2 R82.2 34.08,42.55 36.19,42.55 | C39.2 R85.1 40.86,41.27 D11.A
  Top 0.305: 36.19,42.55 37.13,43.48 R68.P$3 38.1,43.44 38.1,41.59 38.42,41.27 D11.A
N$39
  Top 0.254: R97.1 59.37,29.43 C49.1
N$40
  Top 0.254: IC11.10 55.72,27.84 R99.2 57.89,27.94 R97.2
N$41
  Top 0.254: R73.1 52.17,45.82 51.75,45.4 IC9.2 48.9,45.4 48.68,45.19 R75.1 | R73.1 R71.1 | R72.2 50.58,48.26 R73.1
N$42
  Top 0.254: J20.P3 83.5,29.53 82.55,30.48 R128.2
N$43
  Top 0.254: IC11.2 R89.2 R86.2
N$44
  Top 0.254: C40.1 48.68,40.54 48.9,40.32 IC9.6 51.75,40.32 52.07,40.01 52.07,32.07 51.75,31.75 IC11.4
N$45
  Top 0.254: C47.1 60.54,34.29 R90.1
N$46
  Top 0.254: R124.2 82.55,92.08 83.5,91.12 J16.P3
N$47
  Top 0.254: R56.1 46.36,59.79 C29.1
N$48
  Top 0.254: R87.2 R90.2 IC11.15
N$49
  Top 0.254: C41.1 57.05,40.54 56.83,40.32 IC9.9 54.29,40.32 53.97,40.01 53.97,32.07 54.29,31.75 IC11.13
N$50  (via drill 0.6)
  Top 0.254: R71.2 54.61,49.85 v56.2,48.26 | 55.56,38.99 IC9.8 56.83,39.05 57.05,38.84 C41.2 58.52,38.84 58.74,39.05 58.74,40.01 60.96,42.23 v60.96,46.99 | R128.1 78.74,30.48 76.83,32.38 76.83,39.69 77.15,40.01 77.15,46.67 v76.83,46.99
  Bottom 0.254: v56.2,48.26 57.47,46.99 v60.96,46.99 61.91,46.04 72.07,46.04 73.02,46.99 v76.83,46.99
N$51
  Top 0.254: C48.1 R94.1
N$52
  Top 0.254: IC11.7 49.21,27.94 49,28.16 R98.2 48.16,28.26 47.62,28.26 46.67,29.21 R94.2
N$53
  Top 0.254: R76.2 IC9.13 54.29,45.4 52.7,43.81 52.7,31.43 51.75,30.48 IC11.5
N$54
  Top 0.254: R76.1 R74.2
N$55
  Top 0.254: R73.2 54.61,48.26 55.62,47.25 IC9.14 56.83,46.67 57.15,46.99 R74.1 57.79,47.09 57.79,47.62 58.1,47.94 61.59,47.94 64.13,45.4 67.94,45.4 68.58,44.77 68.58,42.23 67.94,41.59 R88.1 67.84,36.2 67.31,36.2 66.99,35.88 66.99,33.66 66.36,33.02 66.36,30.16 60.96,24.77 58.42,24.77 57.79,25.4 R99.1
N$56
  Top 0.406: JP11.1 JP11.2 47.62,100.33 48.58,99.38 D2.A
N$57  (via drill 0.6)
  Top 0.254: IC11.6 49.21,29.21 48.26,30.16 v48.26,30.48 | R93.2 C46.1 40.64,32.07 | 40.64,32.07 v40.64,30.48 | D17.C 32.52,28.57 33.34,28.57 33.97,29.21 33.97,31.43 34.61,32.07 40.64,32.07
  Bottom 0.254: v40.64,30.48 v48.26,30.48
N$58
  Top 0.254: R65.P$1 22.19,46.31 21.91,46.04 21.91,29.53 22.86,28.57 30.8,28.57 31.43,29.21 31.43,31.96 | 31.43,31.96 R95.2 | 31.43,31.96 31.43,33.34 32.7,34.61 IC10.9 39.05,34.61 | 39.05,34.61 40.43,34.61 C46.2 R93.1 | D12.A 39.05,33.48 39.05,34.61
N$59
  Top 0.254: R70.2 24.98,49.21 20.32,49.21 19.69,48.58 R65.P$2
N$60
  Top 0.254: Q1.C 50.48,4.62 50.48,6.67 51.44,7.62 LED1.K
N$61
  Top 0.254: IC7.7 27.62,57.15 27.41,56.94 R59.2 | IC7.7 28.89,57.09 | R62.1 30.26,54.29 29.53,54.29 28.83,54.99 IC7.7
N$62  (via drill 0.6)
  Top 0.254: J6.P3 6.03,57.15 9.21,53.98 9.21,51.44 11.11,49.53 11.11,33.66 v10.8,33.34 | v23.81,33.97 24.66,33.12 R91.1
  Bottom 0.254: v10.8,33.34 11.11,33.02 22.86,33.02 v23.81,33.97
N$63  (via drill 0.6)
  Top 0.254: J3.P3 10.16,84.14 10.16,75.25 v8.57,73.66 | v33.02,70.17 33.97,69.22 R48.1
  Bottom 0.254: v8.57,73.66 12.06,73.66 13.33,72.39 16.83,72.39 17.46,71.75 18.1,71.75 18.73,72.39 21.91,72.39 22.54,73.03 25.4,73.03 27.3,71.12 30.16,71.12 30.8,70.48 32.7,70.48 v33.02,70.17
N$64
  Top 0.406: JP11.10 JP11.9 57.47,105.09 P1.2
N$65
  Top 0.254: R43.2 35.66,67.31 36.19,67.31 36.51,67.63 36.51,68.26 37.15,68.9 40.32,68.9 40.64,68.58 R34.P$2
N$66  (via drill 0.6)
  Top 0.254: v53.66,54.61 IC8.11 | C23.1 R50.2 24.35,64.98 23.81,64.45 23.81,60.64 22.54,59.37 22.54,56.83 v22.86,56.52 | IC7.1 27.62,64.77 27.41,64.98 C23.1 | D7.C 22.86,76.06 22.86,73.98 26.67,70.17 C23.1
  Bottom 0.254: v53.66,54.61 51.75,52.7 28.58,52.7 24.76,56.52 v22.86,56.52
N$67  (via drill 0.6)
  Top 0.254: R50.1 C23.2 27.41,63.28 27.62,63.5 IC7.2 30.48,63.5 30.8,63.82 v30.8,64.45 R46.2 R45.2 R44.2
  Bottom 0.254: R36.P$3 62.23,67.25 62.23,66.36 61.59,65.72 33.97,65.72 32.7,64.45 v30.8,64.45
N$68  (via drill 0.6)
  Top 0.254: J4.P3 17.78,86.36 17.78,78.11 18.73,77.15 18.73,73.98 19.37,73.34 v19.37,70.8 | v28.58,69.53 29.21,68.9 R45.1
  Bottom 0.254: v19.37,70.8 19.69,71.12 22.54,71.12 23.18,71.75 24.76,71.75 26.99,69.53 v28.58,69.53
N$69
  Top 0.254: R49.2 64.77,65.51 R36.P$2
N$70
  Top 0.254: IC7.13 32.7,63.5 32.38,63.82 R47.2 R48.2 36.3,66.46 37.13,67.3 R34.P$3 | R34.P$3 38.12,67.31 | C24.2 R51.1 39.33,64.98 D8.A 38.42,65.09 38.14,65.36 R34.P$3
N$71
  Top 0.254: R64.1 59.37,54.83 C34.1
N$72
  Top 0.254: IC8.10 56.83,53.34 57.15,53.02 R67.2 R64.2
N$73
  Top 0.254: R38.1 52.07,72.61 52.07,70.17 51.75,69.85 IC6.2 48.9,69.85 48.68,69.64 R40.1 | R38.1 R35.1 | R37.2 50.7,72.71 R38.1
N$74
  Top 0.254: J15.P3 82.65,105.62 R123.2
N$75
  Top 0.254: IC8.2 R56.2 R52.2
N$76
  Top 0.254: C25.1 48.68,64.98 48.9,64.77 IC6.6 51.75,64.77 52.07,64.45 52.07,57.47 51.75,57.15 IC8.4
N$77
  Top 0.254: C30.1 60.54,59.69 R57.1
N$78
  Top 0.254: R125.2 82.23,76.52 83.5,75.25 J17.P3
N$79
  Top 0.254: IC8.15 R57.2 R53.2
N$80
  Top 0.254: C26.1 57.05,64.98 56.83,64.77 IC6.9 54.29,64.77 53.97,64.45 53.97,57.47 54.29,57.15 IC8.13
N$81  (via drill 0.6)
  Top 0.254: IC6.8 56.83,63.5 57.05,63.28 C26.2 58.74,64.24 58.74,64.77 59.69,65.72 60.96,65.72 v60.96,71.44 | v57.47,73.34 56.51,74.3 R35.2 | v78.1,71.44 78.42,71.75 78.42,75.88 79.06,76.52 R125.1
  Bottom 0.254: v57.47,73.34 59.37,71.44 v60.96,71.44 v78.1,71.44
N$82
  Top 0.254: C33.1 R61.1
N$83
  Top 0.254: IC8.7 R66.2 47.84,54.08 46.67,55.24 R61.2
N$84
  Top 0.254: R41.2 IC6.13 53.97,69.85 52.7,68.58 52.7,56.52 52.07,55.88 IC8.5
N$85
  Top 0.254: R41.1 R39.2
N$86
  Top 0.254: R38.2 54.61,72.71 55.62,71.69 IC6.14 56.83,71.12 57.15,71.44 R39.1 57.89,72.17 58.1,72.39 66.04,72.39 68.58,69.85 68.58,65.09 67.94,64.45 R55.1 | R67.1 64.13,53.02 66.68,55.56 66.68,58.1 66.99,58.42 66.99,60.96 67.21,61.17 R55.1 | R55.1 67.94,60.96
N$87  (via drill 0.6)
  Top 0.254: IC8.6 48.9,54.61 v48.26,55.24 | D18.C 34.47,53.02 35.24,53.02 35.56,53.34 35.56,54.93 35.88,55.24 v40.64,55.24 C32.1 R60.2
  Bottom 0.254: v40.64,55.24 v48.26,55.24
N$88
  Top 0.254: 31.43,55.78 R62.2 | 31.43,55.78 31.43,53.34 30.8,52.7 25.72,52.7 25.08,52.07 23.18,52.07 21.91,53.34 21.91,60.64 22.19,60.92 R42.P$1 | 31.43,55.78 31.43,57.15 32.7,58.42 IC7.9 39.05,58.42 | 39.05,58.42 40.54,58.42 C32.2 R60.1 | D9.A 39.05,57.29 39.05,58.42
N$89
  Top 0.254: R58.2 R59.1 27.41,58.63 27.62,58.42 IC7.6
N$90
  Top 0.254: R54.2 19.69,60.74 R42.P$2
N$91
  Top 0.254: IC10.6 27.62,34.61 27.41,34.82 R92.1 R91.2
N$92  (via drill 0.6)
  Top 0.254: R58.1 24.98,56.83 24.45,56.83 23.49,57.78 v23.49,58.42 | v8.89,58.1 9.21,58.42 9.21,70.8 J5.P3
  Bottom 0.254: v23.49,58.42 23.18,58.1 v8.89,58.1
N$93
  Top 0.254: R111.2 63.18,12.38 63.5,12.7 J14.P3
N$94
  Top 0.254: C57.1 R115.1
N$95
  Top 0.254: D12.C IC10.8 32.7,33.34 32.38,33.02 D17.A
N$96
  Top 0.254: 28.89,6.67 IC14.3 26.03,6.67 25.72,6.99 25.19,6.99 R117.2 | 28.89,6.67 IC14.6 33.34,6.67 34.19,7.52 R115.2 | R118.1 28.26,3.81 28.58,4.13 28.58,4.45 28.89,4.76 28.89,6.67
N$97
  Top 0.254: 27.3,2.01 R121.1 27.62,2.12 | 27.62,2.12 27.62,1.59 27.3,1.27 23.49,1.27 22.54,2.22 22.54,7.62 22.86,7.94 IC14.2 | 27.62,2.12 27.72,2.22 28.89,2.22 29.63,2.96 R119.2
N$98
  Top 0.254: C55.1 R113.2 R114.1
N$99
  Top 0.254: R119.1 31.43,3.71 R120.2 32.44,3.96 IC14.5
N$100
  Top 0.254: IC14.1 25.72,9.21 25.54,9.39 D13.A
N$101
  Top 0.254: IC14.7 30.8,7.94 30.3,8.44 D14.A
N$102
  Top 0.254: D13.C 28.58,10.93 28.58,11.43 29.21,12.06 33.34,12.06 | 33.34,12.06 36.83,12.06 37.78,11.11 44.45,11.11 46.99,8.57 R113.1 | D14.C 33.34,10.93 33.34,12.06
N$103
  Top 0.254: R112.1 54.93,9.53 53.97,8.57 LED1.A
N$104
  Top 0.254: R116.2 47.51,7.2 R114.2 47.62,6.88 47.62,6.35 48.11,5.86 Q1.B
N$105
  Top 0.254: D9.C IC7.8 34.03,56 D18.A
OUTPUT  (via drill 0.6)
  Top 0.254: IC13.1 49.21,19.05 49,19.27 R107.2 47.52,19.27 47.31,19.05 v47.31,13.34 48.26,12.38 R111.1 | C57.2 34.71,2.54 35.24,2.54 35.56,2.86 35.56,6.67 39.05,10.16 v44.13,10.16
  Bottom 0.254: v44.13,10.16 v47.31,13.34
PLUS_BUS  (via drill 0.6)
  Top 0.254: v57.79,84.14 57.79,83.19 56.83,82.23 IC5.12 54.29,82.23 53.97,81.92 53.97,78.42 52.7,77.15 49.53,77.15 48.9,76.52 R33.2 | v68.26,83.19 68.26,81.6 66.99,80.33 66.99,73.34 69.85,70.48 69.85,57.78 v69.53,57.47 69.21,57.15 69.21,53.98 66.99,51.75 66.99,49.53 69.85,46.67 69.85,32.7 v69.53,32.38 68.9,31.75 68.9,29.53 66.99,27.62 66.99,25.72 69.85,22.86 69.85,17.78 68.58,16.51 58.74,16.51 58.58,16.35 56.99,16.35 | IC13.6 56.83,16.51 56.99,16.35 | 56.99,16.35 57.05,16.3 R110.1 | R55.2 67.94,58.42 67.63,58.1 v67.63,57.47 | v67.31,32.38 67.31,33.02 67.94,33.66 R88.2
  Bottom 0.254: v68.26,83.19 58.74,83.19 v57.79,84.14 | v69.53,57.47 v67.63,57.47 | v69.53,32.38 v67.31,32.38
VCC  (via drill 0.6)
  Top 0.254: v54.93,90.17 54.71,89.95 C9.1 54.93,88.69 54.93,88.27 55.62,87.57 IC5.16 | 55.88,20.85 C52.1 | C58.+ 56.83,8.26 57.37,8.79 R112.2 | IC8.16 55.56,61.02 55.56,61.59 v56.2,62.23 | v60.64,61.59 C31.1
  Top 0.305: v56.51,96.84 57.47,95.89 57.47,95.35 C5.1 IC3.8 | IC6.4 49.21,67.31 48.36,68.16 C21.1 | v46.36,68.26 47.52,68.26 47.62,68.16 C21.1 | C21.1 47.94,68.26 | v46.36,43.81 47.84,43.81 C36.1 48.36,43.71 49.21,42.86 IC9.4 | C42.1 56.83,37.47 v56.51,37.78 55.62,36.89 IC11.16 | v24.76,86.04 25.93,86.04 C12.1 26.77,85.94 27.62,85.09 IC4.4 | IC7.4 27.62,60.96 26.77,61.81 C27.1 25.93,61.91 v24.76,61.91 | v55.88,21.91 55.88,20.85 | IC13.8 55.66,19.09 C52.1 | 27.62,37.15 IC10.4 | C43.1 25.93,38.1 v24.76,38.1 | IC12.8 32.6,23.97 C50.1 33.34,25.4 v34.29,24.45 | IC14.8 33.34,9.21 33.65,8.89 34.82,8.89 C56.1 36.09,8.99 v36.19,8.89
  Top 0.406: 27.62,37.15 26.77,38 C43.1 | 25.08,100.97 R1.1 | 25.08,100.97 23.81,102.23 17.78,102.23 3.49,87.95 v3.49,86.04 v3.49,60.96 v3.49,35.56 v3.49,25.4 v3.49,10.48 | R112.2 62.87,9.53 63.82,10.48 66.68,10.48 73.34,17.14 v73.34,21.59 v73.34,37.78 v73.34,45.4 v73.34,61.28 v73.34,70.48 v73.34,91.44 v68.9,95.89 64.13,100.65 56.83,100.65 55.56,99.38 D2.C 53.66,99.06 53.66,98.11 53.34,97.79 48.58,97.79 44.77,101.6 31.75,101.6 31.29,101.14 C1.+ | C1.+ 29.53,100.97 | C1.+ 29.35,100.97 25.08,100.97
  Bottom 0.254: v54.93,90.17 57.47,92.71 72.07,92.71 v73.34,91.44 | v56.2,62.23 56.83,61.59 v60.64,61.59 73.02,61.59 v73.34,61.28 | v73.34,37.78 62.23,37.78 61.59,38.42 57.15,38.42 v56.51,37.78
  Bottom 0.305: v68.9,95.89 57.47,95.89 v56.51,96.84 | v46.36,68.26 48.26,70.17 73.02,70.17 v73.34,70.48 | v46.36,43.81 47.94,45.4 v73.34,45.4 | v3.49,86.04 v24.76,86.04 | v24.76,61.91 24.76,63.18 22.86,65.09 16.19,65.09 12.06,60.96 v3.49,60.96 | v55.88,21.91 56.2,21.59 v73.34,21.59 | v24.76,38.1 22.22,35.56 v3.49,35.56 | v3.49,25.4 21.27,25.4 21.59,25.08 33.65,25.08 v34.29,24.45 | v3.49,10.48 33.34,10.48 34.93,8.89 v36.19,8.89
VEE  (via drill 0.6)
  Top 0.254: C51.2 55.56,24.98 | v26.03,16.83 26.35,16.83 27.09,17.57 C53.2
  Top 0.305: 50.16,91.38 IC3.4 50.11,90.64 | IC5.9 57.68,78.42 C20.2 57.89,78.42 v59.69,78.42 | IC6.11 56.83,67.31 57.68,68.16 C22.2 58.52,68.26 v59.69,68.26 | IC8.9 55.62,50.84 C35.2 55.56,50.7 55.46,50.8 54.93,50.8 v53.66,52.07 | IC9.11 56.83,42.86 57.68,43.71 C37.2 58.52,43.81 v59.69,43.81 | IC4.11 35.24,85.09 36.09,85.94 C13.2 36.93,86.04 v38.1,86.04 | 26.99,18.31 C53.2 27.24,18.57 IC12.4 | v1.91,19.05 v1.91,32.38 | v52.39,13.97 C54.2 50.42,14.24 IC13.4 | IC11.9 55.62,25.25 C51.2 56.51,25.08 v56.83,24.77 | 50.11,90.64 C8.2 | 50.11,90.64 50.58,90.17 v51.12,90.17 | 36.19,37.15 IC10.11 | v36.19,37.78 36.19,37.15 | C44.2 36.19,36.3 36.19,37.15 | 36.51,60.22 C28.2 36.3,60.96 | v36.19,61.59 36.3,61.59 36.3,60.96 | 36.3,60.96 IC7.11
  Top 0.406: v74.93,15.24 v74.93,23.81 v74.93,41.91 v74.93,53.02 v74.93,68.9 v74.93,78.42 v74.93,94.3 C2.- 72.22,98.6 66.68,104.14 D1.A P1.1 64.45,105.22 64.45,106.05 63.82,106.68 46.04,106.68 42.55,103.19 v33.65,103.19 16.83,103.19 v1.91,88.27 v1.91,62.23 v1.91,32.38 | v33.65,100.01 R2.1
  Bottom 0.305: v74.93,78.42 v59.69,78.42 | v59.69,68.26 60.33,68.9 v74.93,68.9 | v53.66,52.07 54.61,53.02 v74.93,53.02 | v59.69,43.81 59.69,42.86 60.64,41.91 v74.93,41.91 | v38.1,86.04 28.89,86.04 27.94,87 23.81,87 23.49,86.68 4.76,86.68 3.18,88.27 v1.91,88.27 | v36.19,61.59 28.89,61.59 24.76,65.72 15.87,65.72 11.75,61.59 4.44,61.59 3.81,62.23 v1.91,62.23 | v74.93,23.81 57.79,23.81 v56.83,24.77 | v1.91,32.38 v23.81,32.38 29.21,37.78 v36.19,37.78 | v26.03,16.83 23.81,19.05 v1.91,19.05 | v52.39,13.97 53.66,15.24 v74.93,15.24 | v51.12,90.17 55.25,94.3 v74.93,94.3
  Bottom 0.406: v33.65,103.19 v33.65,100.01

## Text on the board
bPlace: stripe | Red | 0dB | -6dB | Pre-gain
tNames: cc-by-sa Émilie Gillet, 2014. v0.6 | Shelves
bNames: +12V | GND | -12V | Shelves | cc-by-sa Émilie Gillet, | 2014. v6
